# TPT/COMELEC: Modèle générique Généré par gen_hcmos9_ram pour l'ue ELEC342 SOC  V1.0 Fri Jun 17 17:42:05 2011  */
#
VERSION 5.4 ;
NAMESCASESENSITIVE ON ;
DIVIDERCHAR "|" ;
BUSBITCHARS "[]" ;

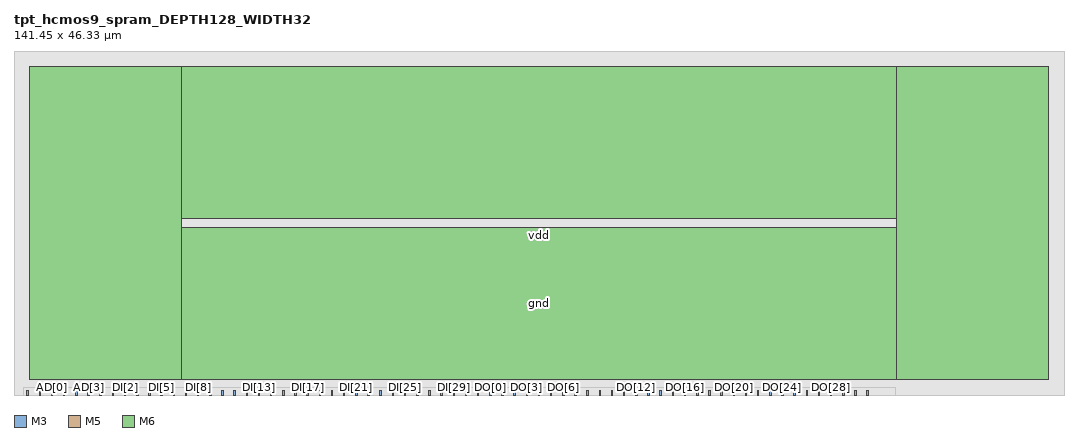
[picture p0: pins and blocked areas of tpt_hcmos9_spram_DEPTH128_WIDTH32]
MACRO tpt_hcmos9_spram_DEPTH128_WIDTH32
    CLASS BLOCK ;
    FOREIGN tpt_hcmos9_spram_DEPTH128_WIDTH32 0.0 0.0 ;
    ORIGIN 0.0 0.0 ;
    SIZE 141.45 BY 46.33 ;
    SYMMETRY X Y R90 ;
    SITE CORE ;


  PIN CK
      FOREIGN CK ;
      DIRECTION INPUT ;
      USE SIGNAL ;
      PORT 
          LAYER M3 ;
	  RECT 1.745 0.000 1.945 0.635 ;
      END
  END CK


  PIN WRITE
      FOREIGN WRITE ;
      DIRECTION INPUT ;
      USE SIGNAL ;
      PORT 
          LAYER M3 ;
	  RECT 3.385 0.000 3.585 0.635 ;
      END
  END WRITE

   
     PIN AD[0]
         FOREIGN AD[0] ;
         DIRECTION INPUT ;
         USE SIGNAL ;
         PORT 
             LAYER M3 ;
   	  RECT 5.025 0.000 5.225 0.635 ;
         END
     END AD[0]
     
   
     PIN AD[1]
         FOREIGN AD[1] ;
         DIRECTION INPUT ;
         USE SIGNAL ;
         PORT 
             LAYER M3 ;
   	  RECT 6.665 0.000 6.865 0.635 ;
         END
     END AD[1]
     
   
     PIN AD[2]
         FOREIGN AD[2] ;
         DIRECTION INPUT ;
         USE SIGNAL ;
         PORT 
             LAYER M3 ;
   	  RECT 8.305 0.000 8.505 0.635 ;
         END
     END AD[2]
     
   
     PIN AD[3]
         FOREIGN AD[3] ;
         DIRECTION INPUT ;
         USE SIGNAL ;
         PORT 
             LAYER M3 ;
   	  RECT 9.945 0.000 10.145 0.635 ;
         END
     END AD[3]
     
   
     PIN DI[0]
         FOREIGN DI[0] ;
         DIRECTION INPUT ;
         USE SIGNAL ;
         PORT 
             LAYER M3 ;
   	  RECT 11.585 0.000 11.785 0.635 ;
         END
     END DI[0]
     
   
     PIN DI[1]
         FOREIGN DI[1] ;
         DIRECTION INPUT ;
         USE SIGNAL ;
         PORT 
             LAYER M3 ;
   	  RECT 13.225 0.000 13.425 0.635 ;
         END
     END DI[1]
     
   
     PIN DI[2]
         FOREIGN DI[2] ;
         DIRECTION INPUT ;
         USE SIGNAL ;
         PORT 
             LAYER M3 ;
   	  RECT 14.865 0.000 15.065 0.635 ;
         END
     END DI[2]
     
   
     PIN DI[3]
         FOREIGN DI[3] ;
         DIRECTION INPUT ;
         USE SIGNAL ;
         PORT 
             LAYER M3 ;
   	  RECT 16.505 0.000 16.705 0.635 ;
         END
     END DI[3]
     
   
     PIN DI[4]
         FOREIGN DI[4] ;
         DIRECTION INPUT ;
         USE SIGNAL ;
         PORT 
             LAYER M3 ;
   	  RECT 18.145 0.000 18.345 0.635 ;
         END
     END DI[4]
     
   
     PIN DI[5]
         FOREIGN DI[5] ;
         DIRECTION INPUT ;
         USE SIGNAL ;
         PORT 
             LAYER M3 ;
   	  RECT 19.785 0.000 19.985 0.635 ;
         END
     END DI[5]
     
   
     PIN DI[6]
         FOREIGN DI[6] ;
         DIRECTION INPUT ;
         USE SIGNAL ;
         PORT 
             LAYER M3 ;
   	  RECT 21.425 0.000 21.625 0.635 ;
         END
     END DI[6]
     
   
     PIN DI[7]
         FOREIGN DI[7] ;
         DIRECTION INPUT ;
         USE SIGNAL ;
         PORT 
             LAYER M3 ;
   	  RECT 23.065 0.000 23.265 0.635 ;
         END
     END DI[7]
     
   
     PIN DI[8]
         FOREIGN DI[8] ;
         DIRECTION INPUT ;
         USE SIGNAL ;
         PORT 
             LAYER M3 ;
   	  RECT 24.705 0.000 24.905 0.635 ;
         END
     END DI[8]
     
   
     PIN DI[9]
         FOREIGN DI[9] ;
         DIRECTION INPUT ;
         USE SIGNAL ;
         PORT 
             LAYER M3 ;
   	  RECT 26.345 0.000 26.545 0.635 ;
         END
     END DI[9]
     
   
     PIN DI[10]
         FOREIGN DI[10] ;
         DIRECTION INPUT ;
         USE SIGNAL ;
         PORT 
             LAYER M3 ;
   	  RECT 27.985 0.000 28.185 0.635 ;
         END
     END DI[10]
     
   
     PIN DI[11]
         FOREIGN DI[11] ;
         DIRECTION INPUT ;
         USE SIGNAL ;
         PORT 
             LAYER M3 ;
   	  RECT 29.625 0.000 29.825 0.635 ;
         END
     END DI[11]
     
   
     PIN DI[12]
         FOREIGN DI[12] ;
         DIRECTION INPUT ;
         USE SIGNAL ;
         PORT 
             LAYER M3 ;
   	  RECT 31.265 0.000 31.465 0.635 ;
         END
     END DI[12]
     
   
     PIN DI[13]
         FOREIGN DI[13] ;
         DIRECTION INPUT ;
         USE SIGNAL ;
         PORT 
             LAYER M3 ;
   	  RECT 32.905 0.000 33.105 0.635 ;
         END
     END DI[13]
     
   
     PIN DI[14]
         FOREIGN DI[14] ;
         DIRECTION INPUT ;
         USE SIGNAL ;
         PORT 
             LAYER M3 ;
   	  RECT 34.545 0.000 34.745 0.635 ;
         END
     END DI[14]
     
   
     PIN DI[15]
         FOREIGN DI[15] ;
         DIRECTION INPUT ;
         USE SIGNAL ;
         PORT 
             LAYER M3 ;
   	  RECT 36.185 0.000 36.385 0.635 ;
         END
     END DI[15]
     
   
     PIN DI[16]
         FOREIGN DI[16] ;
         DIRECTION INPUT ;
         USE SIGNAL ;
         PORT 
             LAYER M3 ;
   	  RECT 37.825 0.000 38.025 0.635 ;
         END
     END DI[16]
     
   
     PIN DI[17]
         FOREIGN DI[17] ;
         DIRECTION INPUT ;
         USE SIGNAL ;
         PORT 
             LAYER M3 ;
   	  RECT 39.465 0.000 39.665 0.635 ;
         END
     END DI[17]
     
   
     PIN DI[18]
         FOREIGN DI[18] ;
         DIRECTION INPUT ;
         USE SIGNAL ;
         PORT 
             LAYER M3 ;
   	  RECT 41.105 0.000 41.305 0.635 ;
         END
     END DI[18]
     
   
     PIN DI[19]
         FOREIGN DI[19] ;
         DIRECTION INPUT ;
         USE SIGNAL ;
         PORT 
             LAYER M3 ;
   	  RECT 42.745 0.000 42.945 0.635 ;
         END
     END DI[19]
     
   
     PIN DI[20]
         FOREIGN DI[20] ;
         DIRECTION INPUT ;
         USE SIGNAL ;
         PORT 
             LAYER M3 ;
   	  RECT 44.385 0.000 44.585 0.635 ;
         END
     END DI[20]
     
   
     PIN DI[21]
         FOREIGN DI[21] ;
         DIRECTION INPUT ;
         USE SIGNAL ;
         PORT 
             LAYER M3 ;
   	  RECT 46.025 0.000 46.225 0.635 ;
         END
     END DI[21]
     
   
     PIN DI[22]
         FOREIGN DI[22] ;
         DIRECTION INPUT ;
         USE SIGNAL ;
         PORT 
             LAYER M3 ;
   	  RECT 47.665 0.000 47.865 0.635 ;
         END
     END DI[22]
     
   
     PIN DI[23]
         FOREIGN DI[23] ;
         DIRECTION INPUT ;
         USE SIGNAL ;
         PORT 
             LAYER M3 ;
   	  RECT 49.305 0.000 49.505 0.635 ;
         END
     END DI[23]
     
   
     PIN DI[24]
         FOREIGN DI[24] ;
         DIRECTION INPUT ;
         USE SIGNAL ;
         PORT 
             LAYER M3 ;
   	  RECT 50.945 0.000 51.145 0.635 ;
         END
     END DI[24]
     
   
     PIN DI[25]
         FOREIGN DI[25] ;
         DIRECTION INPUT ;
         USE SIGNAL ;
         PORT 
             LAYER M3 ;
   	  RECT 52.585 0.000 52.785 0.635 ;
         END
     END DI[25]
     
   
     PIN DI[26]
         FOREIGN DI[26] ;
         DIRECTION INPUT ;
         USE SIGNAL ;
         PORT 
             LAYER M3 ;
   	  RECT 54.225 0.000 54.425 0.635 ;
         END
     END DI[26]
     
   
     PIN DI[27]
         FOREIGN DI[27] ;
         DIRECTION INPUT ;
         USE SIGNAL ;
         PORT 
             LAYER M3 ;
   	  RECT 55.865 0.000 56.065 0.635 ;
         END
     END DI[27]
     
   
     PIN DI[28]
         FOREIGN DI[28] ;
         DIRECTION INPUT ;
         USE SIGNAL ;
         PORT 
             LAYER M3 ;
   	  RECT 57.505 0.000 57.705 0.635 ;
         END
     END DI[28]
     
   
     PIN DI[29]
         FOREIGN DI[29] ;
         DIRECTION INPUT ;
         USE SIGNAL ;
         PORT 
             LAYER M3 ;
   	  RECT 59.145 0.000 59.345 0.635 ;
         END
     END DI[29]
     
   
     PIN DI[30]
         FOREIGN DI[30] ;
         DIRECTION INPUT ;
         USE SIGNAL ;
         PORT 
             LAYER M3 ;
   	  RECT 60.785 0.000 60.985 0.635 ;
         END
     END DI[30]
     
   
     PIN DI[31]
         FOREIGN DI[31] ;
         DIRECTION INPUT ;
         USE SIGNAL ;
         PORT 
             LAYER M3 ;
   	  RECT 62.425 0.000 62.625 0.635 ;
         END
     END DI[31]
     
   
     PIN DO[0]
         FOREIGN DO[0] ;
         DIRECTION OUTPUT ;
         USE SIGNAL ;
         PORT 
             LAYER M3 ;
   	  RECT 64.065 0.000 64.265 0.635 ;
         END
     END DO[0]
     
   
     PIN DO[1]
         FOREIGN DO[1] ;
         DIRECTION OUTPUT ;
         USE SIGNAL ;
         PORT 
             LAYER M3 ;
   	  RECT 65.705 0.000 65.905 0.635 ;
         END
     END DO[1]
     
   
     PIN DO[2]
         FOREIGN DO[2] ;
         DIRECTION OUTPUT ;
         USE SIGNAL ;
         PORT 
             LAYER M3 ;
   	  RECT 67.345 0.000 67.545 0.635 ;
         END
     END DO[2]
     
   
     PIN DO[3]
         FOREIGN DO[3] ;
         DIRECTION OUTPUT ;
         USE SIGNAL ;
         PORT 
             LAYER M3 ;
   	  RECT 68.985 0.000 69.185 0.635 ;
         END
     END DO[3]
     
   
     PIN DO[4]
         FOREIGN DO[4] ;
         DIRECTION OUTPUT ;
         USE SIGNAL ;
         PORT 
             LAYER M3 ;
   	  RECT 70.625 0.000 70.825 0.635 ;
         END
     END DO[4]
     
   
     PIN DO[5]
         FOREIGN DO[5] ;
         DIRECTION OUTPUT ;
         USE SIGNAL ;
         PORT 
             LAYER M3 ;
   	  RECT 72.265 0.000 72.465 0.635 ;
         END
     END DO[5]
     
   
     PIN DO[6]
         FOREIGN DO[6] ;
         DIRECTION OUTPUT ;
         USE SIGNAL ;
         PORT 
             LAYER M3 ;
   	  RECT 73.905 0.000 74.105 0.635 ;
         END
     END DO[6]
     
   
     PIN DO[7]
         FOREIGN DO[7] ;
         DIRECTION OUTPUT ;
         USE SIGNAL ;
         PORT 
             LAYER M3 ;
   	  RECT 75.545 0.000 75.745 0.635 ;
         END
     END DO[7]
     
   
     PIN DO[8]
         FOREIGN DO[8] ;
         DIRECTION OUTPUT ;
         USE SIGNAL ;
         PORT 
             LAYER M3 ;
   	  RECT 77.185 0.000 77.385 0.635 ;
         END
     END DO[8]
     
   
     PIN DO[9]
         FOREIGN DO[9] ;
         DIRECTION OUTPUT ;
         USE SIGNAL ;
         PORT 
             LAYER M3 ;
   	  RECT 78.825 0.000 79.025 0.635 ;
         END
     END DO[9]
     
   
     PIN DO[10]
         FOREIGN DO[10] ;
         DIRECTION OUTPUT ;
         USE SIGNAL ;
         PORT 
             LAYER M3 ;
   	  RECT 80.465 0.000 80.665 0.635 ;
         END
     END DO[10]
     
   
     PIN DO[11]
         FOREIGN DO[11] ;
         DIRECTION OUTPUT ;
         USE SIGNAL ;
         PORT 
             LAYER M3 ;
   	  RECT 82.105 0.000 82.305 0.635 ;
         END
     END DO[11]
     
   
     PIN DO[12]
         FOREIGN DO[12] ;
         DIRECTION OUTPUT ;
         USE SIGNAL ;
         PORT 
             LAYER M3 ;
   	  RECT 83.745 0.000 83.945 0.635 ;
         END
     END DO[12]
     
   
     PIN DO[13]
         FOREIGN DO[13] ;
         DIRECTION OUTPUT ;
         USE SIGNAL ;
         PORT 
             LAYER M3 ;
   	  RECT 85.385 0.000 85.585 0.635 ;
         END
     END DO[13]
     
   
     PIN DO[14]
         FOREIGN DO[14] ;
         DIRECTION OUTPUT ;
         USE SIGNAL ;
         PORT 
             LAYER M3 ;
   	  RECT 87.025 0.000 87.225 0.635 ;
         END
     END DO[14]
     
   
     PIN DO[15]
         FOREIGN DO[15] ;
         DIRECTION OUTPUT ;
         USE SIGNAL ;
         PORT 
             LAYER M3 ;
   	  RECT 88.665 0.000 88.865 0.635 ;
         END
     END DO[15]
     
   
     PIN DO[16]
         FOREIGN DO[16] ;
         DIRECTION OUTPUT ;
         USE SIGNAL ;
         PORT 
             LAYER M3 ;
   	  RECT 90.305 0.000 90.505 0.635 ;
         END
     END DO[16]
     
   
     PIN DO[17]
         FOREIGN DO[17] ;
         DIRECTION OUTPUT ;
         USE SIGNAL ;
         PORT 
             LAYER M3 ;
   	  RECT 91.945 0.000 92.145 0.635 ;
         END
     END DO[17]
     
   
     PIN DO[18]
         FOREIGN DO[18] ;
         DIRECTION OUTPUT ;
         USE SIGNAL ;
         PORT 
             LAYER M3 ;
   	  RECT 93.585 0.000 93.785 0.635 ;
         END
     END DO[18]
     
   
     PIN DO[19]
         FOREIGN DO[19] ;
         DIRECTION OUTPUT ;
         USE SIGNAL ;
         PORT 
             LAYER M3 ;
   	  RECT 95.225 0.000 95.425 0.635 ;
         END
     END DO[19]
     
   
     PIN DO[20]
         FOREIGN DO[20] ;
         DIRECTION OUTPUT ;
         USE SIGNAL ;
         PORT 
             LAYER M3 ;
   	  RECT 96.865 0.000 97.065 0.635 ;
         END
     END DO[20]
     
   
     PIN DO[21]
         FOREIGN DO[21] ;
         DIRECTION OUTPUT ;
         USE SIGNAL ;
         PORT 
             LAYER M3 ;
   	  RECT 98.505 0.000 98.705 0.635 ;
         END
     END DO[21]
     
   
     PIN DO[22]
         FOREIGN DO[22] ;
         DIRECTION OUTPUT ;
         USE SIGNAL ;
         PORT 
             LAYER M3 ;
   	  RECT 100.145 0.000 100.345 0.635 ;
         END
     END DO[22]
     
   
     PIN DO[23]
         FOREIGN DO[23] ;
         DIRECTION OUTPUT ;
         USE SIGNAL ;
         PORT 
             LAYER M3 ;
   	  RECT 101.785 0.000 101.985 0.635 ;
         END
     END DO[23]
     
   
     PIN DO[24]
         FOREIGN DO[24] ;
         DIRECTION OUTPUT ;
         USE SIGNAL ;
         PORT 
             LAYER M3 ;
   	  RECT 103.425 0.000 103.625 0.635 ;
         END
     END DO[24]
     
   
     PIN DO[25]
         FOREIGN DO[25] ;
         DIRECTION OUTPUT ;
         USE SIGNAL ;
         PORT 
             LAYER M3 ;
   	  RECT 105.065 0.000 105.265 0.635 ;
         END
     END DO[25]
     
   
     PIN DO[26]
         FOREIGN DO[26] ;
         DIRECTION OUTPUT ;
         USE SIGNAL ;
         PORT 
             LAYER M3 ;
   	  RECT 106.705 0.000 106.905 0.635 ;
         END
     END DO[26]
     
   
     PIN DO[27]
         FOREIGN DO[27] ;
         DIRECTION OUTPUT ;
         USE SIGNAL ;
         PORT 
             LAYER M3 ;
   	  RECT 108.345 0.000 108.545 0.635 ;
         END
     END DO[27]
     
   
     PIN DO[28]
         FOREIGN DO[28] ;
         DIRECTION OUTPUT ;
         USE SIGNAL ;
         PORT 
             LAYER M3 ;
   	  RECT 109.985 0.000 110.185 0.635 ;
         END
     END DO[28]
     
   
     PIN DO[29]
         FOREIGN DO[29] ;
         DIRECTION OUTPUT ;
         USE SIGNAL ;
         PORT 
             LAYER M3 ;
   	  RECT 111.625 0.000 111.825 0.635 ;
         END
     END DO[29]
     
   
     PIN DO[30]
         FOREIGN DO[30] ;
         DIRECTION OUTPUT ;
         USE SIGNAL ;
         PORT 
             LAYER M3 ;
   	  RECT 113.265 0.000 113.465 0.635 ;
         END
     END DO[30]
     
   
     PIN DO[31]
         FOREIGN DO[31] ;
         DIRECTION OUTPUT ;
         USE SIGNAL ;
         PORT 
             LAYER M3 ;
   	  RECT 114.905 0.000 115.105 0.635 ;
         END
     END DO[31]
     

  PIN gnd
    FOREIGN gnd ;
    DIRECTION INOUT ;
    USE GROUND ;
    SHAPE ABUTMENT ;
    PORT
      LAYER M5 ;
      RECT 2.050 2.050 139.400 22.550 ;
    END
    PORT
      LAYER M5 ;
      RECT 2.050 23.780 139.400 44.280 ;
    END
    PORT
      LAYER M5 ;
      RECT 2.050 2.050 22.550 44.280 ;
    END
    PORT
      LAYER M5 ;
      RECT 118.900 2.050 139.400 44.280 ;
    END
  END gnd


  PIN vdd 
    FOREIGN gnd ;
    DIRECTION INOUT ;
    USE POWER ;
    SHAPE ABUTMENT ;
    PORT
      LAYER M6 ;
      RECT 2.050 2.050 139.400 22.550 ;
    END
    PORT
      LAYER M6 ;
      RECT 2.050 23.780 139.400 44.280 ;
    END
    PORT
      LAYER M6 ;
      RECT 2.050 2.050 22.550 44.280 ;
    END
    PORT
      LAYER M6 ;
      RECT 118.900 2.050 139.400 44.280 ;
    END
  END vdd


  OBS
    LAYER M1 ;
    POLYGON
        0 0
        141.45 0
        141.45 46.33
        0 46.33 ;
    
    LAYER M2 ;
    POLYGON
       1.045 0
       141.45 0
       141.45 46.33
       0 46.33
       0 0.715
       1.045 0.715 ;
    
    LAYER M3 ;
    POLYGON
       141.45 0
       141.45 46.33
       0 46.33
       0 0
       1.335 0
       1.335 1.045
       118.795 1.045
       118.795 0 ;

   END
  END tpt_hcmos9_spram_DEPTH128_WIDTH32
END LIBRARY
